VERSION 5.7 ;
  NOWIREEXTENSIONATPIN ON ;
  DIVIDERCHAR "/" ;
  BUSBITCHARS "[]" ;
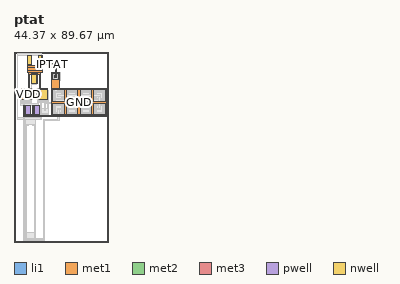
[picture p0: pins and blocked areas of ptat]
MACRO ptat
  CLASS BLOCK ;
  FOREIGN ptat ;
  ORIGIN -0.250 0.450 ;
  SIZE 44.370 BY 89.670 ;
  PIN IPTAT
    ANTENNADIFFAREA 1.522400 ;
    PORT
      LAYER li1 ;
        RECT 13.125 83.490 13.295 87.490 ;
        RECT 19.585 77.365 20.375 78.155 ;
      LAYER met1 ;
        RECT 13.095 84.215 13.325 87.490 ;
        RECT 13.095 83.805 13.485 84.215 ;
        RECT 13.095 83.490 13.495 83.805 ;
        RECT 13.130 83.485 13.495 83.490 ;
        RECT 13.130 83.365 13.485 83.485 ;
        RECT 16.810 81.980 20.380 85.130 ;
        RECT 19.565 77.345 20.395 78.175 ;
      LAYER met2 ;
        RECT 13.205 83.415 20.395 83.855 ;
        RECT 19.970 77.575 20.250 77.945 ;
      LAYER met3 ;
        RECT 19.890 77.390 20.360 83.870 ;
    END
  END IPTAT
  PIN GND
    ANTENNADIFFAREA 4.440000 ;
    PORT
      LAYER pwell ;
        RECT 4.750 59.880 8.100 64.140 ;
        RECT 9.060 59.880 12.410 64.140 ;
      LAYER li1 ;
        RECT 4.890 60.010 5.160 64.010 ;
        RECT 5.480 60.010 5.650 64.010 ;
        RECT 9.200 60.010 9.470 64.010 ;
        RECT 9.790 60.010 9.960 64.010 ;
      LAYER met1 ;
        RECT 18.110 79.590 18.610 79.610 ;
        RECT 21.290 79.590 21.830 79.610 ;
        RECT 18.110 79.110 21.830 79.590 ;
        RECT 18.110 76.410 18.610 79.110 ;
        RECT 21.290 76.410 21.830 79.110 ;
        RECT 18.110 71.970 21.830 76.410 ;
        RECT 43.320 71.970 43.850 71.990 ;
        RECT 17.980 71.430 43.850 71.970 ;
        RECT 18.010 66.010 18.550 71.430 ;
        RECT 23.970 66.010 25.010 71.430 ;
        RECT 30.430 66.010 31.430 71.430 ;
        RECT 36.870 66.010 37.870 71.430 ;
        RECT 43.320 66.010 43.850 71.430 ;
        RECT 18.010 64.980 43.850 66.010 ;
        RECT 4.890 61.745 5.160 64.010 ;
        RECT 5.450 61.745 5.680 64.010 ;
        RECT 9.200 61.885 9.470 64.010 ;
        RECT 9.760 61.885 9.990 64.010 ;
        RECT 4.735 60.010 5.680 61.745 ;
        RECT 9.070 60.010 9.990 61.885 ;
        RECT 4.735 59.610 5.635 60.010 ;
        RECT 9.070 59.610 9.935 60.010 ;
        RECT 4.735 59.450 9.935 59.610 ;
        RECT 18.010 59.540 18.550 64.980 ;
        RECT 23.970 59.540 25.010 64.980 ;
        RECT 30.430 59.540 31.430 64.980 ;
        RECT 36.870 59.540 37.870 64.980 ;
        RECT 43.320 59.540 43.850 64.980 ;
        RECT 18.010 59.450 43.860 59.540 ;
        RECT 4.735 58.980 43.860 59.450 ;
        RECT 4.735 58.890 18.460 58.980 ;
        RECT 4.735 58.880 9.935 58.890 ;
    END
  END GND
  PIN VDD
    ANTENNADIFFAREA 7.590900 ;
    PORT
      LAYER nwell ;
        RECT 6.435 82.685 8.325 87.675 ;
        RECT 11.625 82.680 13.515 87.670 ;
        RECT 8.530 74.130 11.420 79.120 ;
        RECT 3.805 66.570 8.975 71.800 ;
        RECT 11.030 66.570 16.200 71.800 ;
      LAYER li1 ;
        RECT 6.655 83.495 6.825 87.495 ;
        RECT 11.845 83.490 12.015 87.490 ;
        RECT 6.625 82.875 8.135 83.145 ;
        RECT 11.815 82.870 13.325 83.140 ;
        RECT 8.720 78.660 11.230 78.930 ;
        RECT 11.030 74.310 11.200 78.310 ;
        RECT 3.995 71.340 8.785 71.610 ;
        RECT 11.220 71.340 16.010 71.610 ;
      LAYER met1 ;
        RECT 6.625 85.240 6.855 87.495 ;
        RECT 11.815 85.605 12.045 87.490 ;
        RECT 6.410 83.495 6.855 85.240 ;
        RECT 6.410 83.145 6.810 83.495 ;
        RECT 11.565 83.490 12.045 85.605 ;
        RECT 6.410 82.990 8.135 83.145 ;
        RECT 11.565 83.140 11.965 83.490 ;
        RECT 11.565 82.990 13.325 83.140 ;
        RECT 6.410 81.745 13.480 82.990 ;
        RECT 6.445 80.625 13.480 81.745 ;
        RECT 6.480 79.410 13.480 80.625 ;
        RECT 6.860 78.660 12.950 79.410 ;
        RECT 6.860 71.610 7.525 78.660 ;
        RECT 10.990 78.080 11.265 78.660 ;
        RECT 11.000 74.310 11.230 78.080 ;
        RECT 12.260 71.610 12.925 78.660 ;
        RECT 3.995 71.340 8.785 71.610 ;
        RECT 11.220 71.340 16.010 71.610 ;
    END
  END VDD
  OBS
      LAYER pwell ;
        RECT 17.990 78.985 21.970 79.750 ;
        RECT 17.990 76.535 18.755 78.985 ;
        RECT 21.205 76.535 21.970 78.985 ;
        RECT 17.990 75.770 21.970 76.535 ;
        RECT 17.920 71.295 43.940 72.060 ;
        RECT 17.920 66.125 18.685 71.295 ;
        RECT 23.855 66.125 25.125 71.295 ;
        RECT 30.295 66.125 31.565 71.295 ;
        RECT 36.735 66.125 38.005 71.295 ;
        RECT 43.175 66.125 43.940 71.295 ;
        RECT 17.920 64.855 43.940 66.125 ;
        RECT 17.920 59.685 18.685 64.855 ;
        RECT 23.855 59.685 25.125 64.855 ;
        RECT 30.295 59.685 31.565 64.855 ;
        RECT 36.735 59.685 38.005 64.855 ;
        RECT 43.175 59.685 43.940 64.855 ;
        RECT 17.920 58.920 43.940 59.685 ;
        RECT 5.800 56.810 10.200 57.240 ;
        RECT 5.800 2.110 6.230 56.810 ;
        RECT 9.770 2.110 10.200 56.810 ;
        RECT 5.800 1.680 10.200 2.110 ;
      LAYER li1 ;
        RECT 6.880 87.705 7.880 87.935 ;
        RECT 12.070 87.700 13.070 87.930 ;
        RECT 7.935 83.495 8.105 87.495 ;
        RECT 18.120 79.115 21.840 79.620 ;
        RECT 8.750 74.310 8.920 78.310 ;
        RECT 18.120 76.405 18.625 79.115 ;
        RECT 18.935 78.445 21.025 78.805 ;
        RECT 18.935 77.075 19.295 78.445 ;
        RECT 20.665 77.075 21.025 78.445 ;
        RECT 18.935 76.715 21.025 77.075 ;
        RECT 21.335 76.405 21.840 79.115 ;
        RECT 18.120 75.900 21.840 76.405 ;
        RECT 8.975 73.870 10.975 74.100 ;
        RECT 18.050 71.435 43.810 71.930 ;
        RECT 4.025 66.750 4.195 70.750 ;
        RECT 6.305 66.750 6.475 70.750 ;
        RECT 8.585 66.750 8.755 70.750 ;
        RECT 11.250 66.750 11.420 70.750 ;
        RECT 13.530 66.750 13.700 70.750 ;
        RECT 15.810 66.750 15.980 70.750 ;
        RECT 4.250 65.910 8.530 66.140 ;
        RECT 11.475 65.910 15.755 66.140 ;
        RECT 18.050 65.985 18.545 71.435 ;
        RECT 18.865 70.755 23.675 71.115 ;
        RECT 18.865 66.665 19.225 70.755 ;
        RECT 19.535 66.975 23.005 70.445 ;
        RECT 23.315 66.665 23.675 70.755 ;
        RECT 18.865 66.305 23.675 66.665 ;
        RECT 23.995 65.985 24.985 71.435 ;
        RECT 25.305 70.755 30.115 71.115 ;
        RECT 25.305 66.665 25.665 70.755 ;
        RECT 25.975 66.975 29.445 70.445 ;
        RECT 29.755 66.665 30.115 70.755 ;
        RECT 25.305 66.305 30.115 66.665 ;
        RECT 30.435 65.985 31.425 71.435 ;
        RECT 31.745 70.755 36.555 71.115 ;
        RECT 31.745 66.665 32.105 70.755 ;
        RECT 32.415 66.975 35.885 70.445 ;
        RECT 36.195 66.665 36.555 70.755 ;
        RECT 31.745 66.305 36.555 66.665 ;
        RECT 36.875 65.985 37.865 71.435 ;
        RECT 38.185 70.755 42.995 71.115 ;
        RECT 38.185 66.665 38.545 70.755 ;
        RECT 38.855 66.975 42.325 70.445 ;
        RECT 42.635 66.665 42.995 70.755 ;
        RECT 38.185 66.305 42.995 66.665 ;
        RECT 43.315 65.985 43.810 71.435 ;
        RECT 18.050 64.995 43.810 65.985 ;
        RECT 5.705 64.220 7.705 64.450 ;
        RECT 10.015 64.220 12.015 64.450 ;
        RECT 7.760 60.010 7.930 64.010 ;
        RECT 12.070 60.010 12.240 64.010 ;
        RECT 18.050 59.545 18.545 64.995 ;
        RECT 18.865 64.315 23.675 64.675 ;
        RECT 18.865 60.225 19.225 64.315 ;
        RECT 19.535 60.535 23.005 64.005 ;
        RECT 23.315 60.225 23.675 64.315 ;
        RECT 18.865 59.865 23.675 60.225 ;
        RECT 23.995 59.545 24.985 64.995 ;
        RECT 25.305 64.315 30.115 64.675 ;
        RECT 25.305 60.225 25.665 64.315 ;
        RECT 25.975 60.535 29.445 64.005 ;
        RECT 29.755 60.225 30.115 64.315 ;
        RECT 25.305 59.865 30.115 60.225 ;
        RECT 30.435 59.545 31.425 64.995 ;
        RECT 31.745 64.315 36.555 64.675 ;
        RECT 31.745 60.225 32.105 64.315 ;
        RECT 32.415 60.535 35.885 64.005 ;
        RECT 36.195 60.225 36.555 64.315 ;
        RECT 31.745 59.865 36.555 60.225 ;
        RECT 36.875 59.545 37.865 64.995 ;
        RECT 38.185 64.315 42.995 64.675 ;
        RECT 38.185 60.225 38.545 64.315 ;
        RECT 38.855 60.535 42.325 64.005 ;
        RECT 42.635 60.225 42.995 64.315 ;
        RECT 38.185 59.865 42.995 60.225 ;
        RECT 43.315 59.545 43.810 64.995 ;
        RECT 18.050 59.050 43.810 59.545 ;
        RECT 5.930 56.940 10.070 57.110 ;
        RECT 5.930 1.980 6.100 56.940 ;
        RECT 6.580 54.300 6.930 56.460 ;
        RECT 9.070 54.300 9.420 56.460 ;
        RECT 9.900 1.980 10.070 56.940 ;
        RECT 5.930 1.810 10.070 1.980 ;
      LAYER met1 ;
        RECT 1.735 88.350 13.130 88.360 ;
        RECT 1.730 87.710 13.130 88.350 ;
        RECT 1.730 58.080 2.110 87.710 ;
        RECT 6.880 87.685 7.880 87.710 ;
        RECT 8.055 87.495 8.425 87.710 ;
        RECT 12.070 87.680 13.070 87.710 ;
        RECT 7.905 85.310 8.425 87.495 ;
        RECT 7.905 83.495 8.135 85.310 ;
        RECT 18.960 78.790 21.010 78.820 ;
        RECT 18.950 78.440 21.010 78.790 ;
        RECT 8.720 75.230 8.950 78.310 ;
        RECT 18.950 77.070 19.290 78.440 ;
        RECT 20.670 77.070 21.010 78.440 ;
        RECT 18.950 76.730 21.010 77.070 ;
        RECT 18.960 76.720 21.010 76.730 ;
        RECT 19.900 76.700 20.160 76.720 ;
        RECT 8.375 74.310 8.950 75.230 ;
        RECT 8.375 74.140 8.920 74.310 ;
        RECT 8.375 74.120 9.220 74.140 ;
        RECT 8.375 73.850 10.975 74.120 ;
        RECT 8.375 73.805 9.220 73.850 ;
        RECT 3.995 70.920 8.785 71.150 ;
        RECT 3.100 64.875 3.745 67.310 ;
        RECT 3.995 66.750 4.225 70.920 ;
        RECT 6.275 67.520 6.505 70.750 ;
        RECT 8.555 69.775 8.785 70.920 ;
        RECT 11.220 71.100 16.010 71.150 ;
        RECT 18.870 71.110 23.660 71.130 ;
        RECT 25.330 71.110 30.120 71.130 ;
        RECT 11.220 70.920 16.490 71.100 ;
        RECT 8.370 69.415 8.945 69.775 ;
        RECT 6.115 66.925 6.690 67.520 ;
        RECT 6.275 66.350 6.505 66.925 ;
        RECT 8.555 66.750 8.785 69.415 ;
        RECT 11.220 66.750 11.450 70.920 ;
        RECT 13.500 69.775 13.730 70.750 ;
        RECT 13.335 69.415 13.910 69.775 ;
        RECT 13.500 66.350 13.730 69.415 ;
        RECT 15.780 66.750 16.490 70.920 ;
        RECT 4.250 65.890 8.530 66.160 ;
        RECT 11.475 65.890 15.755 66.160 ;
        RECT 4.260 65.490 8.500 65.890 ;
        RECT 11.495 65.490 15.735 65.890 ;
        RECT 3.100 64.205 12.025 64.875 ;
        RECT 5.705 64.200 7.975 64.205 ;
        RECT 10.015 64.200 12.015 64.205 ;
        RECT 7.690 62.190 7.975 64.200 ;
        RECT 12.040 62.395 12.270 64.010 ;
        RECT 15.915 62.395 16.490 66.750 ;
        RECT 18.870 70.750 23.670 71.110 ;
        RECT 18.870 66.670 19.210 70.750 ;
        RECT 19.745 67.185 22.795 70.235 ;
        RECT 23.330 66.670 23.670 70.750 ;
        RECT 18.870 66.310 23.670 66.670 ;
        RECT 25.320 70.750 30.120 71.110 ;
        RECT 31.720 71.110 36.510 71.130 ;
        RECT 38.180 71.110 42.970 71.130 ;
        RECT 31.720 70.750 36.540 71.110 ;
        RECT 38.180 70.750 42.990 71.110 ;
        RECT 25.320 66.670 25.660 70.750 ;
        RECT 26.185 67.185 29.235 70.235 ;
        RECT 29.750 66.670 30.090 70.750 ;
        RECT 31.760 66.670 32.100 70.750 ;
        RECT 32.625 67.185 35.675 70.235 ;
        RECT 36.200 66.670 36.540 70.750 ;
        RECT 38.200 66.700 38.540 70.750 ;
        RECT 39.065 67.185 42.115 70.235 ;
        RECT 42.650 66.700 42.990 70.750 ;
        RECT 25.320 66.310 30.120 66.670 ;
        RECT 31.760 66.310 36.560 66.670 ;
        RECT 38.180 66.320 42.990 66.700 ;
        RECT 38.200 66.310 38.540 66.320 ;
        RECT 42.650 66.310 42.990 66.320 ;
        RECT 18.870 66.290 23.660 66.310 ;
        RECT 25.330 66.290 30.120 66.310 ;
        RECT 31.770 66.290 36.560 66.310 ;
        RECT 20.320 64.670 20.580 64.700 ;
        RECT 18.890 64.660 23.680 64.670 ;
        RECT 25.330 64.660 30.120 64.670 ;
        RECT 31.770 64.660 36.560 64.680 ;
        RECT 7.730 60.010 7.960 62.190 ;
        RECT 12.040 60.010 16.490 62.395 ;
        RECT 12.110 59.880 16.490 60.010 ;
        RECT 18.870 64.290 23.680 64.660 ;
        RECT 25.320 64.290 30.120 64.660 ;
        RECT 31.760 64.300 36.560 64.660 ;
        RECT 38.180 64.660 42.970 64.680 ;
        RECT 38.180 64.300 42.990 64.660 ;
        RECT 18.870 60.240 19.210 64.290 ;
        RECT 19.745 60.745 22.795 63.795 ;
        RECT 23.330 60.240 23.670 64.290 ;
        RECT 18.870 59.860 23.680 60.240 ;
        RECT 25.320 60.230 25.660 64.290 ;
        RECT 26.185 60.745 29.235 63.795 ;
        RECT 29.750 60.230 30.090 64.290 ;
        RECT 31.760 60.230 32.100 64.300 ;
        RECT 32.625 60.745 35.675 63.795 ;
        RECT 36.200 60.230 36.540 64.300 ;
        RECT 38.210 60.230 38.550 64.300 ;
        RECT 39.065 60.745 42.115 63.795 ;
        RECT 42.650 60.230 42.990 64.300 ;
        RECT 25.320 59.860 30.120 60.230 ;
        RECT 31.760 59.860 36.560 60.230 ;
        RECT 25.330 59.850 30.120 59.860 ;
        RECT 31.770 59.850 36.560 59.860 ;
        RECT 38.200 59.850 42.990 60.230 ;
        RECT 1.720 57.370 13.330 58.080 ;
        RECT 5.700 54.800 10.450 57.370 ;
        RECT 14.285 56.770 21.525 57.270 ;
        RECT 6.630 54.325 6.880 54.800 ;
        RECT 9.120 54.325 9.370 54.800 ;
        RECT 6.230 1.050 9.750 4.070 ;
        RECT 14.300 1.050 14.700 56.770 ;
        RECT 4.950 0.510 14.700 1.050 ;
        RECT 4.950 0.490 14.660 0.510 ;
      LAYER met2 ;
        RECT 8.375 74.900 8.530 75.230 ;
        RECT 8.375 74.580 8.705 74.900 ;
        RECT 8.375 69.755 8.530 74.580 ;
        RECT 19.330 70.700 20.800 77.020 ;
        RECT 8.375 69.640 8.695 69.755 ;
        RECT 13.445 69.640 13.705 69.735 ;
        RECT 8.375 69.495 13.765 69.640 ;
        RECT 8.375 69.435 8.695 69.495 ;
        RECT 8.375 69.430 8.530 69.435 ;
        RECT 13.445 69.415 13.705 69.495 ;
        RECT 21.190 68.525 21.470 68.895 ;
        RECT 27.570 68.485 27.850 68.855 ;
        RECT 34.120 68.525 34.400 68.895 ;
        RECT 40.310 68.485 40.590 68.855 ;
        RECT 6.320 67.305 6.580 67.420 ;
        RECT 3.100 67.160 6.690 67.305 ;
        RECT 3.280 66.945 3.540 67.160 ;
        RECT 6.320 67.100 6.580 67.160 ;
        RECT 12.710 57.360 13.330 65.990 ;
        RECT 19.970 65.560 41.660 66.680 ;
        RECT 14.550 65.540 41.660 65.560 ;
        RECT 14.540 64.960 41.660 65.540 ;
        RECT 14.540 61.770 15.070 64.960 ;
        RECT 19.970 64.290 41.660 64.960 ;
        RECT 21.100 62.155 21.380 62.525 ;
        RECT 27.470 62.175 27.750 62.545 ;
        RECT 33.870 62.205 34.150 62.575 ;
        RECT 40.350 62.155 40.630 62.525 ;
        RECT 21.030 56.825 21.310 57.195 ;
      LAYER met3 ;
        RECT 20.960 68.390 40.910 68.950 ;
        RECT 4.940 0.520 5.300 65.870 ;
        RECT 40.150 62.600 40.860 68.390 ;
        RECT 20.940 62.040 40.910 62.600 ;
        RECT 20.940 56.780 21.500 62.040 ;
  END
END ptat
END LIBRARY

